(* Logix 5000 project; controller V16_L55_Blank vendor 1 type 14 code 51 rev 16.2; software revision 16.04; part 2 of 5 *)
(* tags used below, declared in another part *)
   ConnectionOutput : INT[248];
   StoppedTimer : TIMER;
   ProveEnabled : BOOL;
   NotStoppedTimer : TIMER;
   CycleCounterPreviousStopped : INT;
   MJFAULTS : DINT[12];
   ForceReset : BOOL;
   AvoidBufferOverflowFault : DINT;   // Need this to prevent Overflow Minor Fault
   AOI56EAFC : AOI56EAFC;
(* AOI56EAFC, continued *)

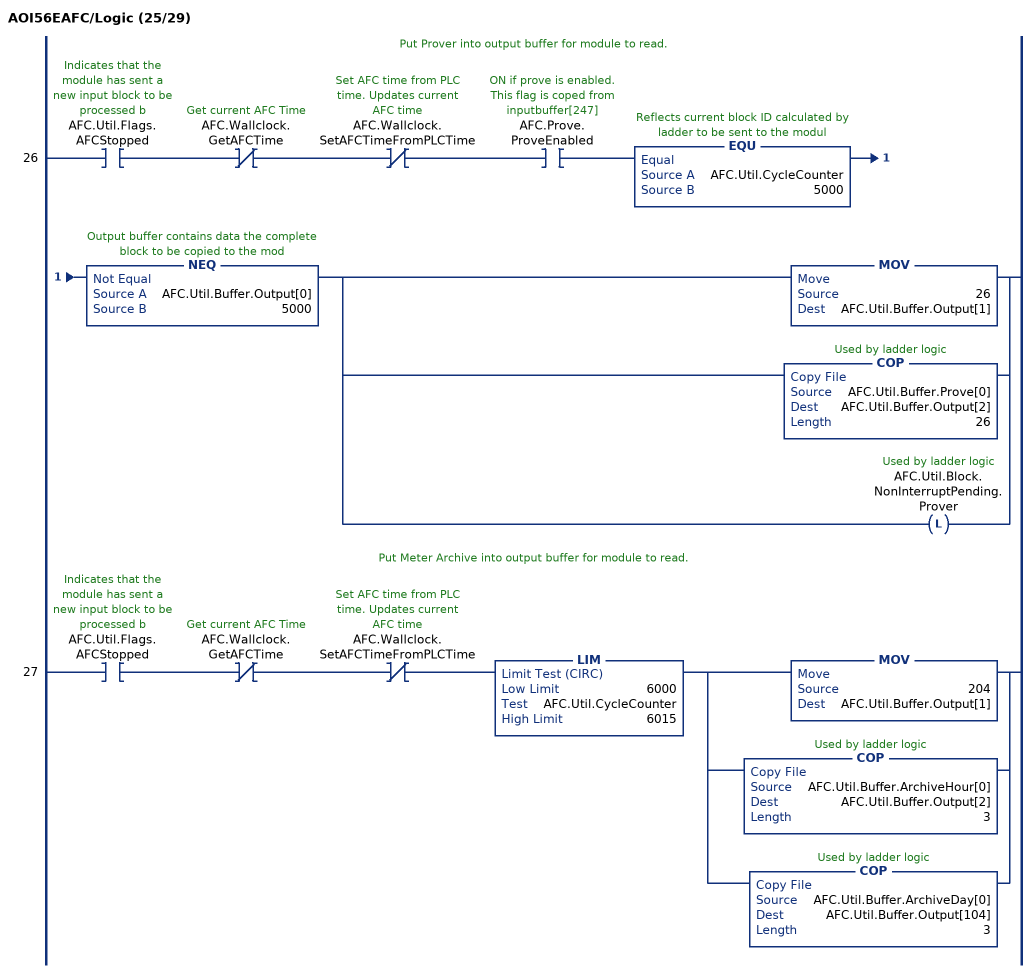
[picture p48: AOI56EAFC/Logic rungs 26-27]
   // Put Prover into output buffer for module to read.
   26: XIC(AFC.Util.Flags.AFCStopped)XIO(AFC.Wallclock.GetAFCTime)XIO(AFC.Wallclock.SetAFCTimeFromPLCTime)XIC(AFC.Prove.ProveEnabled)EQU(AFC.Util.CycleCounter,5000)NEQ(AFC.Util.Buffer.Output[0],5000)[MOV(26,AFC.Util.Buffer.Output[1]) ,COP(AFC.Util.Buffer.Prove[0],AFC.Util.Buffer.Output[2],26) ,OTL(AFC.Util.Block.NonInterruptPending.Prover) ];
   // Put Meter Archive into output buffer for module to read.
   27: XIC(AFC.Util.Flags.AFCStopped)XIO(AFC.Wallclock.GetAFCTime)XIO(AFC.Wallclock.SetAFCTimeFromPLCTime)LIM(6000,AFC.Util.CycleCounter,6015)[MOV(204,AFC.Util.Buffer.Output[1]) ,COP(AFC.Util.Buffer.ArchiveHour[0],AFC.Util.Buffer.Output[2],3) ,COP(AFC.Util.Buffer.ArchiveDay[0],AFC.Util.Buffer.Output[104],3) ];
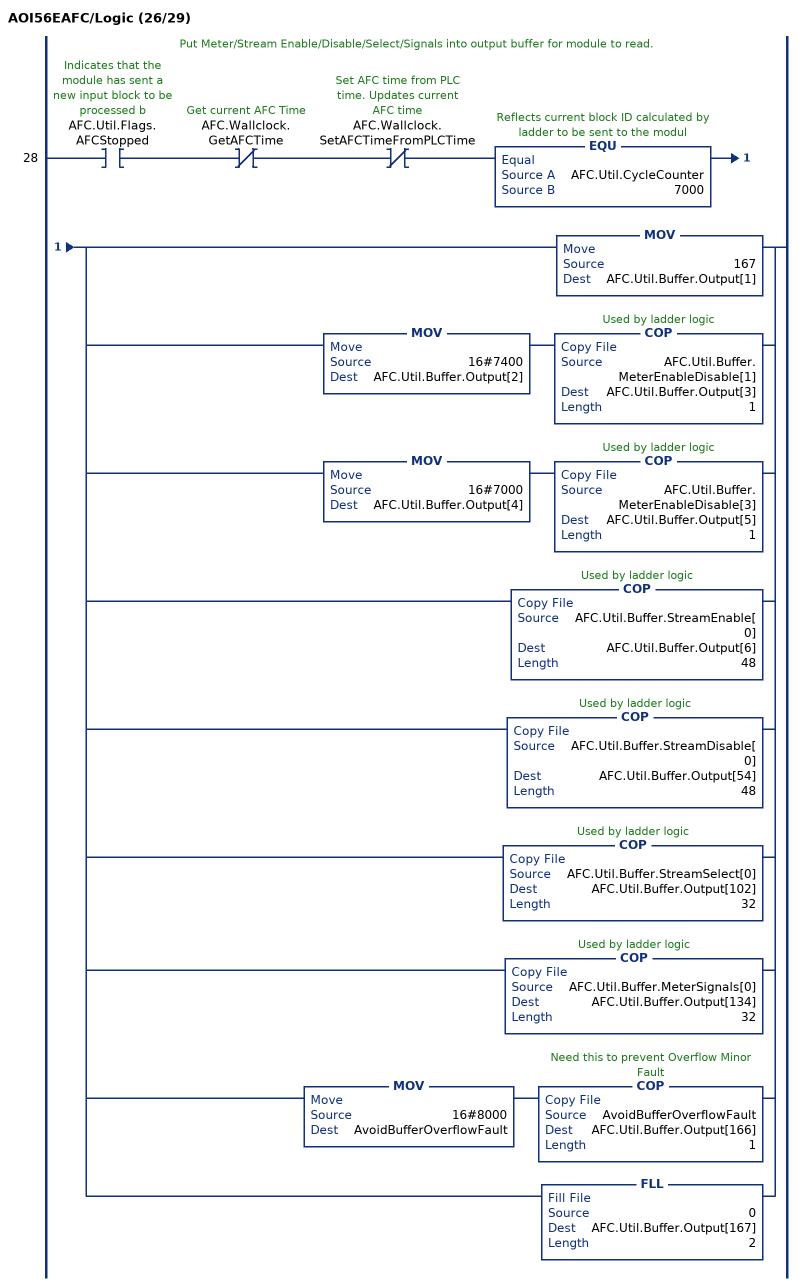
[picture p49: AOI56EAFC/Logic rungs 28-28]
   // Put Meter/Stream Enable/Disable/Select/Signals into output buffer for module to read.
   28: XIC(AFC.Util.Flags.AFCStopped)XIO(AFC.Wallclock.GetAFCTime)XIO(AFC.Wallclock.SetAFCTimeFromPLCTime)EQU(AFC.Util.CycleCounter,7000)[MOV(167,AFC.Util.Buffer.Output[1]) ,MOV(16#7400,AFC.Util.Buffer.Output[2]) COP(AFC.Util.Buffer.MeterEnableDisable[1],AFC.Util.Buffer.Output[3],1) ,MOV(16#7000,AFC.Util.Buffer.Output[4]) COP(AFC.Util.Buffer.MeterEnableDisable[3],AFC.Util.Buffer.Output[5],1) ,COP(AFC.Util.Buffer.StreamEnable[0],AFC.Util.Buffer.Output[6],48) ,COP(AFC.Util.Buffer.StreamDisable[0],AFC.Util.Buffer.Output[54],48) ,COP(AFC.Util.Buffer.StreamSelect[0],AFC.Util.Buffer.Output[102],32) ,COP(AFC.Util.Buffer.MeterSignals[0],AFC.Util.Buffer.Output[134],32) ,[MOV(16#8000,AvoidBufferOverflowFault) COP(AvoidBufferOverflowFault,AFC.Util.Buffer.Output[166],1) ,FLL(0,AFC.Util.Buffer.Output[167],2) ] ];
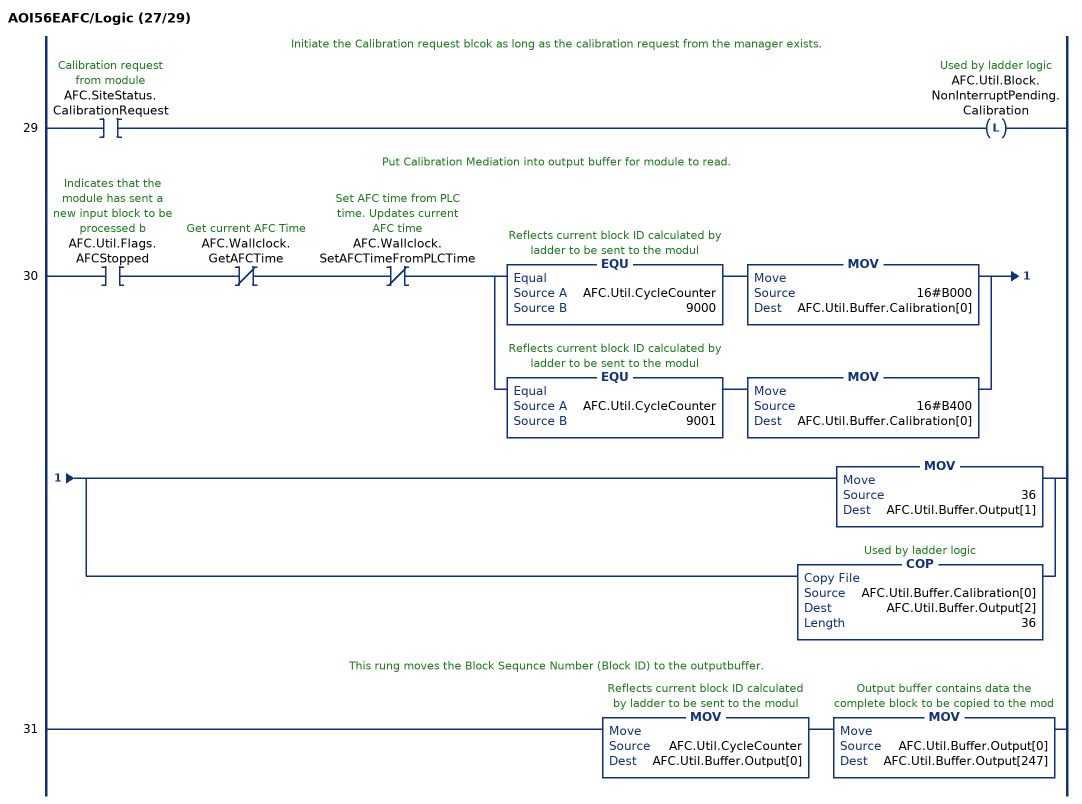
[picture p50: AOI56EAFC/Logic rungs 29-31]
   // Initiate the Calibration request blcok as long as the calibration request from the manager exists.
   29: XIC(AFC.SiteStatus.CalibrationRequest)OTL(AFC.Util.Block.NonInterruptPending.Calibration);
   // Put Calibration Mediation into output buffer for module to read.
   30: XIC(AFC.Util.Flags.AFCStopped)XIO(AFC.Wallclock.GetAFCTime)XIO(AFC.Wallclock.SetAFCTimeFromPLCTime)[EQU(AFC.Util.CycleCounter,9000) MOV(16#B000,AFC.Util.Buffer.Calibration[0]) ,EQU(AFC.Util.CycleCounter,9001) MOV(16#B400,AFC.Util.Buffer.Calibration[0]) ][MOV(36,AFC.Util.Buffer.Output[1]) ,COP(AFC.Util.Buffer.Calibration[0],AFC.Util.Buffer.Output[2],36) ];
   // This rung moves the Block Sequnce Number (Block ID) to the outputbuffer.
   31: MOV(AFC.Util.CycleCounter,AFC.Util.Buffer.Output[0])MOV(AFC.Util.Buffer.Output[0],AFC.Util.Buffer.Output[247]);
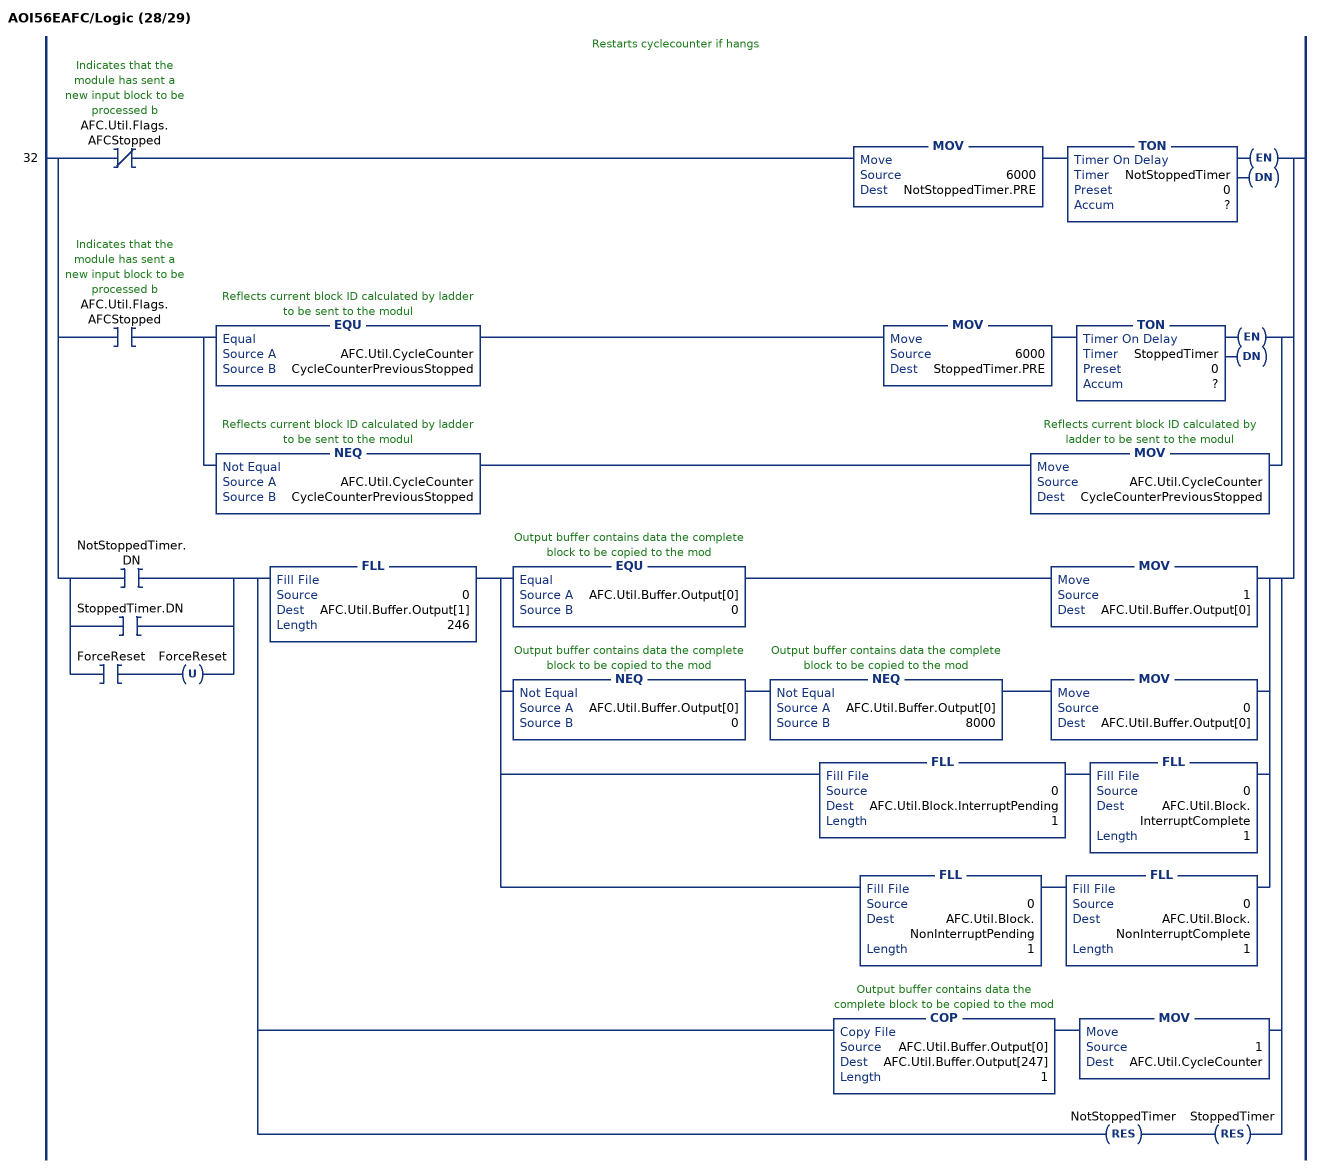
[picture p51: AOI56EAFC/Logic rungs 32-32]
   // Restarts cyclecounter if hangs
   32: [XIO(AFC.Util.Flags.AFCStopped) MOV(6000,NotStoppedTimer.PRE) TON(NotStoppedTimer,?,?) ,XIC(AFC.Util.Flags.AFCStopped) [EQU(AFC.Util.CycleCounter,CycleCounterPreviousStopped) MOV(6000,StoppedTimer.PRE) TON(StoppedTimer,?,?) ,NEQ(AFC.Util.CycleCounter,CycleCounterPreviousStopped) MOV(AFC.Util.CycleCounter,CycleCounterPreviousStopped) ] ,[[XIC(NotStoppedTimer.DN) ,XIC(StoppedTimer.DN) ] ,XIC(ForceReset) OTU(ForceReset) ] [FLL(0,AFC.Util.Buffer.Output[1],246) [EQU(AFC.Util.Buffer.Output[0],0) MOV(1,AFC.Util.Buffer.Output[0]) ,NEQ(AFC.Util.Buffer.Output[0],0) NEQ(AFC.Util.Buffer.Output[0],8000) MOV(0,AFC.Util.Buffer.Output[0]) ,FLL(0,AFC.Util.Block.InterruptPending,1) FLL(0,AFC.Util.Block.InterruptComplete,1) ,FLL(0,AFC.Util.Block.NonInterruptPending,1) FLL(0,AFC.Util.Block.NonInterruptComplete,1) ] ,COP(AFC.Util.Buffer.Output[0],AFC.Util.Buffer.Output[247],1) MOV(1,AFC.Util.CycleCounter) ,RES(NotStoppedTimer) RES(StoppedTimer) ] ];
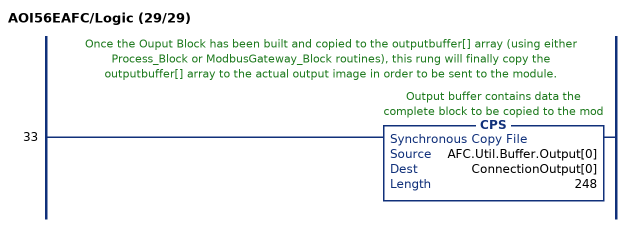
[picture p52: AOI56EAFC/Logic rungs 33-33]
   // Once the Ouput Block has been built and copied to the outputbuffer[] array (using either Process_Block or ModbusGateway_Block routines), this rung will finally copy the outputbuffer[] array to the actual output image in order to be sent to the module.
   33: CPS(AFC.Util.Buffer.Output[0],ConnectionOutput[0],248);
END_ROUTINE

ROUTINE Prescan   (* ladder *)
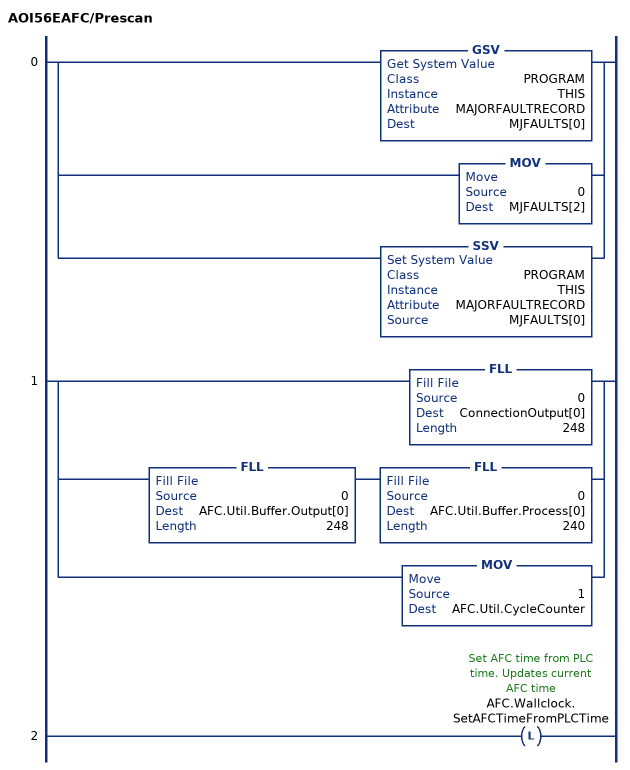
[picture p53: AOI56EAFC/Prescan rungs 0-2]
   0: [GSV(PROGRAM,THIS,MAJORFAULTRECORD,MJFAULTS[0]) ,MOV(0,MJFAULTS[2]) ,SSV(PROGRAM,THIS,MAJORFAULTRECORD,MJFAULTS[0]) ];
   1: [FLL(0,ConnectionOutput[0],248) ,FLL(0,AFC.Util.Buffer.Output[0],248) FLL(0,AFC.Util.Buffer.Process[0],240) ,MOV(1,AFC.Util.CycleCounter) ];
   2: OTL(AFC.Wallclock.SetAFCTimeFromPLCTime);
END_ROUTINE
END_ADD_ON_INSTRUCTION

ADD_ON_INSTRUCTION AOI56EAFCMeterDifferentialGas   (* revision 1.8, ExecutePrescan *)
// Add-On instruction for the MVI56E-AFC.
// Differential Gas Meter
// Revision note:
// Corrected/Reverted ProcessInputBlockID Tag Data Type from INT to DINT.
// Help:
// Compatible with version 4.03 of MVI56E-AFC firmware or higher.
// v1.2: Remove Calculation Results. Add Backplane Return. Add Stale Data
// v1.3: Added Flow Rate Process Input and Flow Rate Alarm Controller Tags for Flow Rate Devices (and not just for Differential Pressure)
// v1.4: Addition of default process input backplane return data mapping.
// v1.5: Made correlation changes between the Module Archive Default UDTs and the AOI Archive Default UDTs.
// v1.6: Made changes to the Flow Rate Primary Input Block ID Insertion in Rung 8 (Removed +1),
// Modified ProcessInputBlockID Tag Data Type from DINT to INT. and modified ModbusGatewayConfig UDT StartRegister Tag Data Type from INT to DINT.
// v1.7:  Updated Tags names AFCMeterXXYYYYYY.BackPlaneReturn.ProcessInputs to AFCMeterXXYYYYYY.BackPlaneReturn.Standard and AFCMeterXXYYYYYY.BackPlaneReturn.ComponentAnalysis
//  to AFCMeterXXYYYYYY.BackPlaneReturn.Extended
// v1.8:  Corrected/Reverted ProcessInputBlockID Tag Data Type from INT to DINT.
VAR_IN_OUT
   ConnectionInput : INT[250]; {required}
   AFC : AFCEModuleDef; {required}
   AFCMeter : AFCEMeterDifferentialGas; {required}
END_VAR
VAR_INPUT
   MeterNumber : SINT; {required}   // Meter Number Set to a number between 1 and 16
END_VAR
VAR
   TimestampBuffer : DINT;
   StreamSelectedShift : DINT;
   StreamSelectBuffer : INT;
   EnabledStatusBuffer : INT;
   StreamSelectBlockID : DINT;
   StreamNumberShift : DINT;
   StreamErrorBuffer : DINT;
   StreamEnableBlockID : DINT;
   StreamEnableBitPosition : DINT;
   StreamDisableBlockID : DINT;
   ProfileBuffer : SINT[2];
   ProcessInputBlockID : DINT;
   CalibrationHandleBuffer : INT;
   AnalysisGroupBitPosition : INT;
   ProcessAlarmShifter : DINT;
   ProcessAlarmBuffer : DINT;
   MeterSignaltBlockID : DINT;
   MeterNumberShift : DINT;
   MeterNumberBitPostition : DINT;
   Inputbuffer : INT[250];
   CurrentHourlyAgeONS : BOOL;
   CurrentHourlyAge : DINT;
   CurrentDailyAgeONS : BOOL;
   CurrentDailyAge : DINT;
   ClearMeterSignal : BOOL;   // Repeat the meter signal block with cleared signal bits. This allows repeat triggering of a signal.
   CalibrationMeterNumberBuffer : DINT;
   CalibrationMediationPending : BOOL;
   CalibrationInputScalingIndex : DINT;
   AnalysisErrorBuffer : INT;
   ArchiveStream : DINT;
   ArchiveMeterStatusRaw : DINT;
   ArchiveMeterStatusActiveStream : DINT;
   ArchiveHourlyRawSize : DINT;
   ArchiveHourlyOffset : DINT;
   ArchiveHourlyDefaultSize : DINT;
   ArchiveDailyRawSize : DINT;
   ArchiveDailyOffset : DINT;
   ArchiveDailyDefaultSize : DINT;
   ArchiveCompleteBitCheck : DINT;
   ArchiveBlockID : DINT;
   AnalysisGroupShift : DINT;
   AnalysisCompleteBitCheck : DINT;
   AnalysisBufferOffset : DINT;
   AnalysisBlockID : DINT;
   AFCStopped : BOOL;
   AFCInputDataAvailable : BOOL;
END_VAR

ROUTINE Logic   (* ladder *)
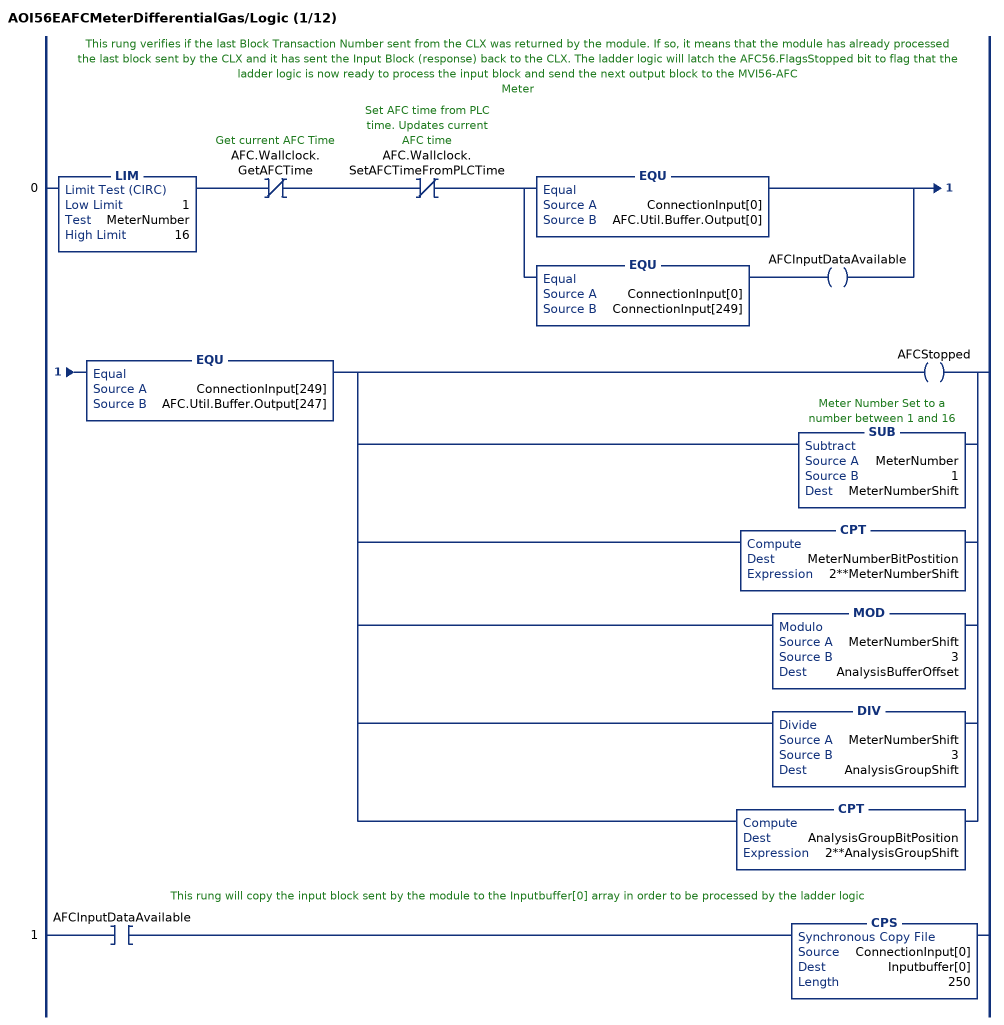
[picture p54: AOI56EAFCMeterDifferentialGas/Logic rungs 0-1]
   // This rung verifies if the last Block Transaction Number sent from the CLX was returned by the module. If so, it means that the module has already processed the last block sent by the CLX and it has sent the Input Block (response) back to the CLX. The ladder logic will latch the AFC56.FlagsStopped bit to flag that the ladder logic is now ready to process the input block and send the next output block to the MVI56-AFC
   // Meter
   0: LIM(1,MeterNumber,16)XIO(AFC.Wallclock.GetAFCTime)XIO(AFC.Wallclock.SetAFCTimeFromPLCTime)[EQU(ConnectionInput[0],AFC.Util.Buffer.Output[0]) ,EQU(ConnectionInput[0],ConnectionInput[249]) OTE(AFCInputDataAvailable) ]EQU(ConnectionInput[249],AFC.Util.Buffer.Output[247])[OTE(AFCStopped) ,SUB(MeterNumber,1,MeterNumberShift) ,CPT(MeterNumberBitPostition,2**MeterNumberShift) ,MOD(MeterNumberShift,3,AnalysisBufferOffset) ,DIV(MeterNumberShift,3,AnalysisGroupShift) ,CPT(AnalysisGroupBitPosition,2**AnalysisGroupShift) ];
   // This rung will copy the input block sent by the module to the Inputbuffer[0] array in order to be processed by the ladder logic
   1: XIC(AFCInputDataAvailable)CPS(ConnectionInput[0],Inputbuffer[0],250);
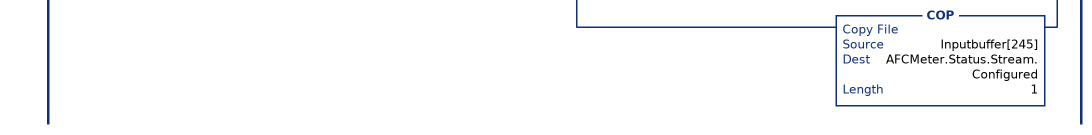
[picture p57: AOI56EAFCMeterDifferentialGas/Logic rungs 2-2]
   // Read process input backplane return and
   // meter profile (when block ID matches meter number).
   2: XIC(AFCInputDataAvailable)LIM(1,Inputbuffer[0],16)[COP(Inputbuffer[3+MeterNumberShift*15],AFCMeter.BackPlaneReturn.StandardRaw[0],14) ,COP(AFCMeter.BackPlaneReturn.StandardRaw[0],AFCMeter.BackPlaneReturn.StandardDefault,1) ,COP(Inputbuffer[247],AFC.SiteStatus,1) ,COP(Inputbuffer[248],AFC.MeterAlarms,1) ,EQU(Inputbuffer[0],MeterNumber) [COP(Inputbuffer[243],ProfileBuffer[0],2) ,[XIC(ProfileBuffer[0].0) OTL(AFCMeter.Status.Meter.EnableAlarm) ,XIO(ProfileBuffer[0].0) OTU(AFCMeter.Status.Meter.EnableAlarm) ] ,[XIC(ProfileBuffer[0].1) OTL(AFCMeter.Status.Meter.Enabled) ,XIO(ProfileBuffer[0].1) OTU(AFCMeter.Status.Meter.Enabled) ] ,[[XIC(ProfileBuffer[0].4) OTL(AFCMeter.Profile.MeterType) ,XIO(ProfileBuffer[0].4) OTU(AFCMeter.Profile.MeterType) ] ,[XIC(ProfileBuffer[0].5) OTL(AFCMeter.Profile.ProductGroup) ,XIO(ProfileBuffer[0].5) OTU(AFCMeter.Profile.ProductGroup) ] ,[XIC(ProfileBuffer[0].6) OTL(AFCMeter.Profile.PrimaryInput) ,XIO(ProfileBuffer[0].6) OTU(AFCMeter.Profile.PrimaryInput) ] ] ,[[XIC(ProfileBuffer[0].4) ,XIC(ProfileBuffer[0].5) ] OTL(AFCMeter.Profile.AOIMismatch) ,XIO(ProfileBuffer[0].4) XIO(ProfileBuffer[0].5) OTU(AFCMeter.Profile.AOIMismatch) ] ,MVM(ProfileBuffer[1],16#1F,ProfileBuffer[1]) ADD(ProfileBuffer[1],1,AFCMeter.Status.Stream.Active) ,COP(Inputbuffer[244],AFCMeter.Status.Stream.Enabled,1) ,COP(Inputbuffer[245],AFCMeter.Status.Stream.Configured,1) ] ];
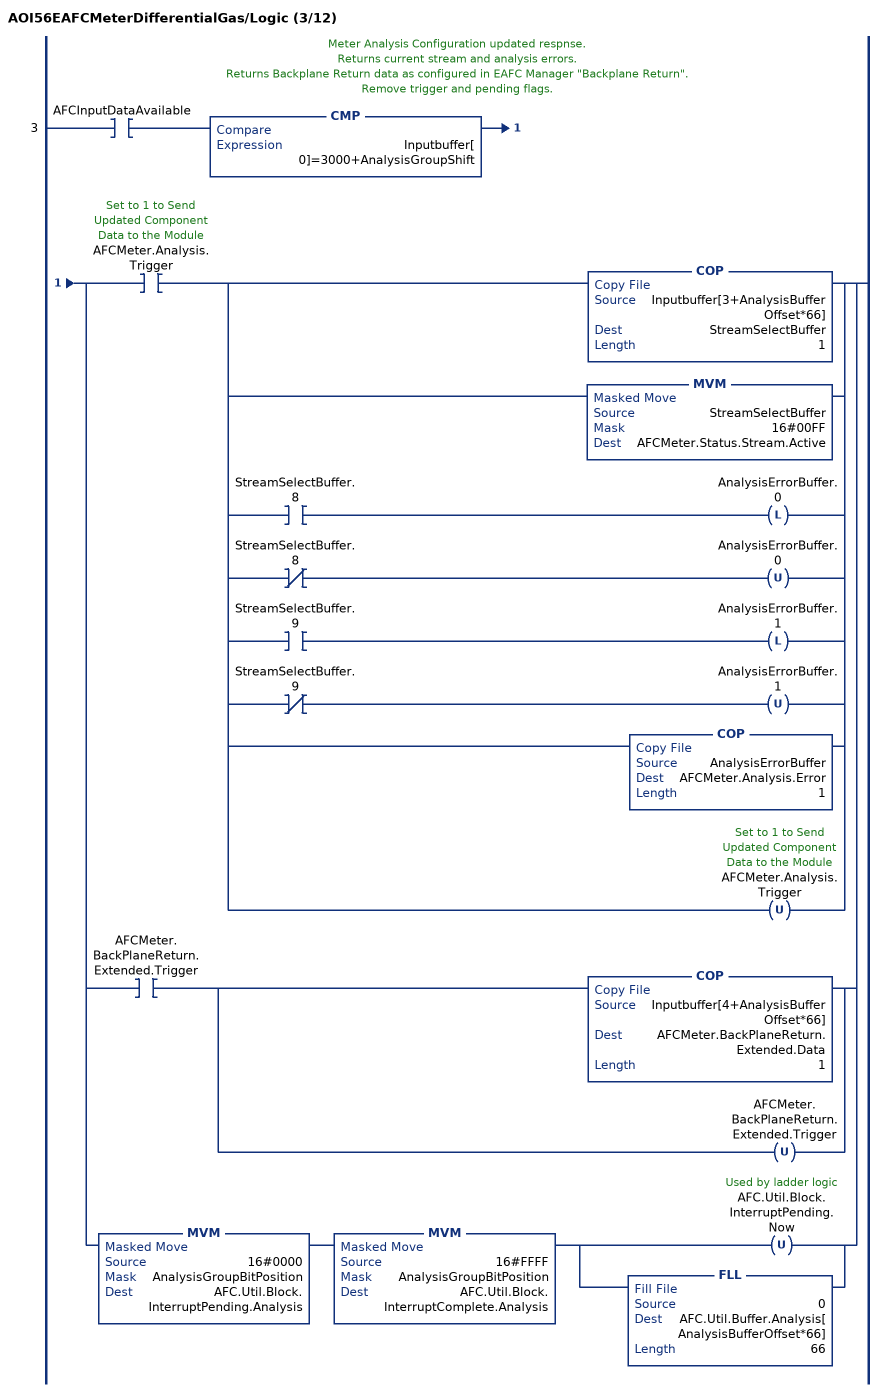
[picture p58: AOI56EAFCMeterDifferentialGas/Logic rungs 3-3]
   // Meter Analysis Configuration updated respnse.
   // Returns current stream and analysis errors.
   // Returns Backplane Return data as configured in EAFC Manager "Backplane Return".
   // Remove trigger and pending flags.
   3: XIC(AFCInputDataAvailable)CMP(Inputbuffer[0]=3000+AnalysisGroupShift)[XIC(AFCMeter.Analysis.Trigger) [COP(Inputbuffer[3+AnalysisBufferOffset*66],StreamSelectBuffer,1) ,MVM(StreamSelectBuffer,16#00FF,AFCMeter.Status.Stream.Active) ,[XIC(StreamSelectBuffer.8) OTL(AnalysisErrorBuffer.0) ,XIO(StreamSelectBuffer.8) OTU(AnalysisErrorBuffer.0) ] ,[XIC(StreamSelectBuffer.9) OTL(AnalysisErrorBuffer.1) ,XIO(StreamSelectBuffer.9) OTU(AnalysisErrorBuffer.1) ] ,COP(AnalysisErrorBuffer,AFCMeter.Analysis.Error,1) ,OTU(AFCMeter.Analysis.Trigger) ] ,XIC(AFCMeter.BackPlaneReturn.Extended.Trigger) [COP(Inputbuffer[4+AnalysisBufferOffset*66],AFCMeter.BackPlaneReturn.Extended.Data,1) ,OTU(AFCMeter.BackPlaneReturn.Extended.Trigger) ] ,MVM(16#0000,AnalysisGroupBitPosition,AFC.Util.Block.InterruptPending.Analysis) MVM(16#FFFF,AnalysisGroupBitPosition,AFC.Util.Block.InterruptComplete.Analysis) [OTU(AFC.Util.Block.InterruptPending.Now) ,FLL(0,AFC.Util.Buffer.Analysis[AnalysisBufferOffset*66],66) ] ];
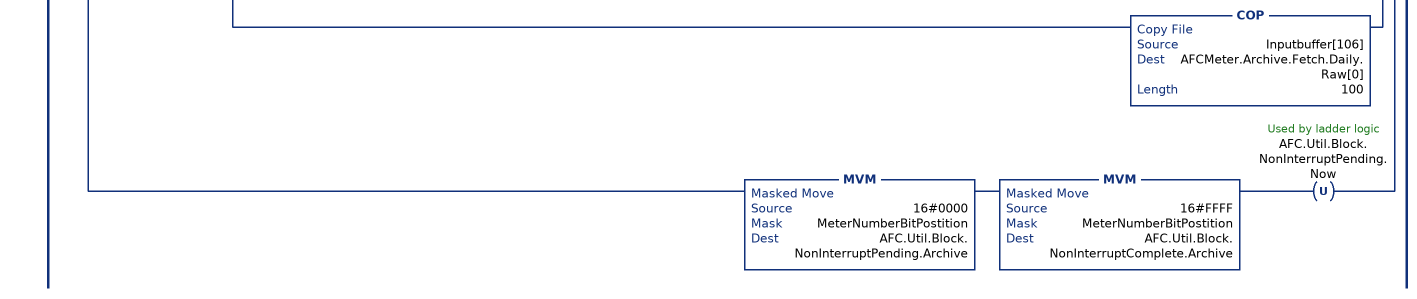
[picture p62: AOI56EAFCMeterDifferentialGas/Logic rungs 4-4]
   // Archive Fetch to default and raw UDT's.
   // Get archive alarms.
   // Remove trigger and pending flags.
   4: XIC(AFCInputDataAvailable)CMP(Inputbuffer[0]=6000+MeterNumberShift)[XIC(AFCMeter.Archive.Fetch.Hourly.Trigger) [OTU(AFCMeter.Archive.Fetch.Hourly.Trigger) ,[[XIC(Inputbuffer[3].0) OTL(AFCMeter.Archive.Fetch.Hourly.Error.ArchiveSelectionInvalid) ,XIO(Inputbuffer[3].0) OTU(AFCMeter.Archive.Fetch.Hourly.Error.ArchiveSelectionInvalid) ] ,[XIC(Inputbuffer[3].1) OTL(AFCMeter.Archive.Fetch.Hourly.Error.AgeOutsideSize) ,XIO(Inputbuffer[3].1) OTU(AFCMeter.Archive.Fetch.Hourly.Error.AgeOutsideSize) ] ,[XIC(Inputbuffer[3].2) OTL(AFCMeter.Archive.Fetch.Hourly.Error.ArchiveNeverWritten) ,XIO(Inputbuffer[3].2) OTU(AFCMeter.Archive.Fetch.Hourly.Error.ArchiveNeverWritten) ] ] ,COP(Inputbuffer[4],AFCMeter.Archive.Fetch.Hourly.Default.ClosingTimestamp,1) ,COP(Inputbuffer[6],AFCMeter.Archive.Fetch.Hourly.Default.CumulativeActiveStreams,1) ,COP(Inputbuffer[7],ArchiveMeterStatusActiveStream,1) [MVM(ArchiveMeterStatusActiveStream,16#0000000F,ArchiveStream) ADD(ArchiveStream,1,AFCMeter.Archive.Fetch.Hourly.Default.CurrentActiveStream) ,MVM(ArchiveMeterStatusActiveStream,16#0000FF00,ArchiveMeterStatusRaw) DIV(ArchiveMeterStatusRaw,256,ArchiveMeterStatusRaw) COP(ArchiveMeterStatusRaw,AFCMeter.Archive.Fetch.Hourly.Default.MeterStatus,1) ] ,COP(Inputbuffer[8],AFCMeter.Archive.Fetch.Hourly.Default.FlowingPeriod,48) ,COP(Inputbuffer[4],AFCMeter.Archive.Fetch.Hourly.Raw[0],100) ] ,XIC(AFCMeter.Archive.Fetch.Daily.Trigger) [OTU(AFCMeter.Archive.Fetch.Daily.Trigger) ,[[XIC(Inputbuffer[105].0) OTL(AFCMeter.Archive.Fetch.Daily.Error.ArchiveSelectionInvalid) ,XIO(Inputbuffer[105].0) OTU(AFCMeter.Archive.Fetch.Daily.Error.ArchiveSelectionInvalid) ] ,[XIC(Inputbuffer[105].1) OTL(AFCMeter.Archive.Fetch.Daily.Error.AgeOutsideSize) ,XIO(Inputbuffer[105].1) OTU(AFCMeter.Archive.Fetch.Daily.Error.AgeOutsideSize) ] ,[XIC(Inputbuffer[105].2) OTL(AFCMeter.Archive.Fetch.Daily.Error.ArchiveNeverWritten) ,XIO(Inputbuffer[105].2) OTU(AFCMeter.Archive.Fetch.Daily.Error.ArchiveNeverWritten) ] ] ,COP(Inputbuffer[106],AFCMeter.Archive.Fetch.Daily.Default.ClosingTimestamp,1) ,COP(Inputbuffer[108],AFCMeter.Archive.Fetch.Daily.Default.CumulativeActiveStreams,1) ,COP(Inputbuffer[109],ArchiveMeterStatusActiveStream,1) [MVM(ArchiveMeterStatusActiveStream,16#0000000F,ArchiveStream) ADD(ArchiveStream,1,AFCMeter.Archive.Fetch.Daily.Default.CurrentActiveStream) ,MVM(ArchiveMeterStatusActiveStream,16#0000FF00,ArchiveMeterStatusRaw) DIV(ArchiveMeterStatusRaw,256,ArchiveMeterStatusRaw) COP(ArchiveMeterStatusRaw,AFCMeter.Archive.Fetch.Daily.Default.MeterStatus,1) ] ,COP(Inputbuffer[110],AFCMeter.Archive.Fetch.Daily.Default.FlowingPeriod,48) ,COP(Inputbuffer[106],AFCMeter.Archive.Fetch.Daily.Raw[0],100) ] ,MVM(16#0000,MeterNumberBitPostition,AFC.Util.Block.NonInterruptPending.Archive) MVM(16#FFFF,MeterNumberBitPostition,AFC.Util.Block.NonInterruptComplete.Archive) OTU(AFC.Util.Block.NonInterruptPending.Now) ];
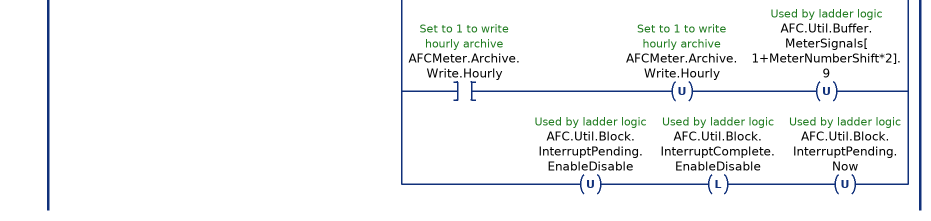
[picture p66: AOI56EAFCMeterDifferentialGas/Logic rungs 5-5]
   // Meter status and stream status.
   // Remove trigger and pending flags.
   5: XIC(AFCInputDataAvailable)EQU(Inputbuffer[0],7000)[[MVM(Inputbuffer[3],MeterNumberBitPostition,EnabledStatusBuffer) ,[NEQ(EnabledStatusBuffer,0) OTL(AFCMeter.Status.Meter.Enabled) ,EQU(EnabledStatusBuffer,0) OTU(AFCMeter.Status.Meter.Enabled) ] ,OTU(AFCMeter.Control.Meter.Enable) MVM(16#0000,MeterNumberBitPostition,AFC.Util.Buffer.MeterEnableDisable[1]) ,OTU(AFCMeter.Control.Meter.Disable) MVM(16#0000,MeterNumberBitPostition,AFC.Util.Buffer.MeterEnableDisable[3]) ] ,[XIC(AFCMeter.Control.Stream.EnableSelected) [COP(Inputbuffer[7+MeterNumberShift*3],AFCMeter.Status.Stream.Enabled,1) ,COP(Inputbuffer[8+MeterNumberShift*3],AFCMeter.Status.Stream.Configured,1) ,OTU(AFCMeter.Control.Stream.EnableSelected) OTU(AFCMeter.Control.Stream.DisableSelected) ] ,XIC(AFCMeter.Control.Stream.DisableSelected) [COP(Inputbuffer[55+MeterNumberShift*3],AFCMeter.Status.Stream.Enabled,1) ,COP(Inputbuffer[56+MeterNumberShift*3],AFCMeter.Status.Stream.Configured,1) ,OTU(AFCMeter.Control.Stream.EnableSelected) OTU(AFCMeter.Control.Stream.DisableSelected) ] ] ,[OTU(AFCMeter.Control.Stream.SetSelectedToActive) ,COP(Inputbuffer[103+MeterNumberShift*2],StreamSelectBuffer,1) ,[XIC(StreamSelectBuffer.8) OTL(StreamErrorBuffer.0) ,XIO(StreamSelectBuffer.8) OTU(StreamErrorBuffer.0) ] ,[XIC(StreamSelectBuffer.9) OTL(StreamErrorBuffer.1) ,XIO(StreamSelectBuffer.9) OTU(StreamErrorBuffer.1) ] ,[XIC(StreamSelectBuffer.10) OTL(StreamErrorBuffer.2) ,XIO(StreamSelectBuffer.10) OTU(StreamErrorBuffer.2) ] ,[XIC(StreamSelectBuffer.11) OTL(StreamErrorBuffer.3) ,XIO(StreamSelectBuffer.11) OTU(StreamErrorBuffer.3) ] ,MVM(StreamSelectBuffer,16#000F,StreamSelectedShift) ADD(StreamSelectedShift,1,AFCMeter.Status.Stream.Active) ,COP(StreamErrorBuffer,AFCMeter.Status.Stream.EnableAlarm,1) ] ,[XIC(AFCMeter.Control.ResetAccumulators.ResetAccumulator1) OTU(AFCMeter.Control.ResetAccumulators.ResetAccumulator1) OTU(AFC.Util.Buffer.MeterSignals[1+MeterNumberShift*2].4) ,XIC(AFCMeter.Control.ResetAccumulators.ResetAccumulator2) OTU(AFCMeter.Control.ResetAccumulators.ResetAccumulator2) OTU(AFC.Util.Buffer.MeterSignals[1+MeterNumberShift*2].5) ,XIC(AFCMeter.Control.ResetAccumulators.ResetAccumulator3) OTU(AFCMeter.Control.ResetAccumulators.ResetAccumulator3) OTU(AFC.Util.Buffer.MeterSignals[1+MeterNumberShift*2].6) ,XIC(AFCMeter.Control.ResetAccumulators.ResetAccumulator4) OTU(AFCMeter.Control.ResetAccumulators.ResetAccumulator4) OTU(AFC.Util.Buffer.MeterSignals[1+MeterNumberShift*2].7) ,XIC(AFCMeter.Archive.Write.Daily) OTU(AFCMeter.Archive.Write.Daily) OTU(AFC.Util.Buffer.MeterSignals[1+MeterNumberShift*2].8) ,XIC(AFCMeter.Archive.Write.Hourly) OTU(AFCMeter.Archive.Write.Hourly) OTU(AFC.Util.Buffer.MeterSignals[1+MeterNumberShift*2].9) ] ,OTU(AFC.Util.Block.InterruptPending.EnableDisable) OTL(AFC.Util.Block.InterruptComplete.EnableDisable) OTU(AFC.Util.Block.InterruptPending.Now) ];
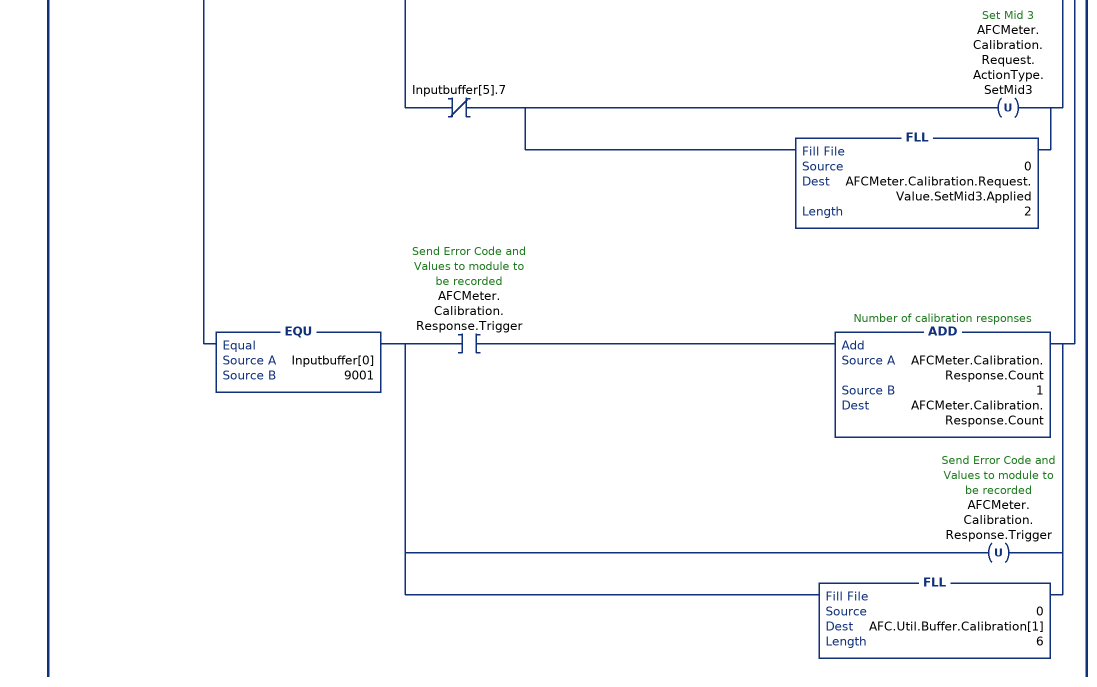
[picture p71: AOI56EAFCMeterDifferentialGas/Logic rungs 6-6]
   // Meter transmitter calibration.
   6: XIC(AFCInputDataAvailable)[EQU(Inputbuffer[0],9000) ,EQU(Inputbuffer[0],9001) ][MVM(Inputbuffer[3],16#0F00,CalibrationMeterNumberBuffer) ,DIV(CalibrationMeterNumberBuffer,16#100,CalibrationMeterNumberBuffer) ]EQU(CalibrationMeterNumberBuffer,MeterNumberShift)XIO(Inputbuffer[3].14)[EQU(Inputbuffer[0],9000) [XIO(CalibrationMediationPending) ADD(AFCMeter.Calibration.Request.Count,1,AFCMeter.Calibration.Request.Count) ,OTL(CalibrationMediationPending) [COP(Inputbuffer[3],CalibrationHandleBuffer,1) ,MVM(CalibrationHandleBuffer,16#000F,CalibrationInputScalingIndex) ] ,[EQU(CalibrationInputScalingIndex,0) [OTL(AFCMeter.Calibration.Request.ProcessVariable.DifferentialPressure) ,OTU(AFCMeter.Calibration.Request.ProcessVariable.Temperature) ,OTU(AFCMeter.Calibration.Request.ProcessVariable.Pressure) ] ,EQU(CalibrationInputScalingIndex,1) [OTL(AFCMeter.Calibration.Request.ProcessVariable.Temperature) ,OTU(AFCMeter.Calibration.Request.ProcessVariable.DifferentialPressure) ,OTU(AFCMeter.Calibration.Request.ProcessVariable.Pressure) ] ,EQU(CalibrationInputScalingIndex,2) [OTL(AFCMeter.Calibration.Request.ProcessVariable.Pressure) ,OTU(AFCMeter.Calibration.Request.ProcessVariable.DifferentialPressure) ,OTU(AFCMeter.Calibration.Request.ProcessVariable.Temperature) ] ] ,[[XIC(Inputbuffer[5].2) [OTL(AFCMeter.Calibration.Request.ActionType.ZeroShift) ,COP(Inputbuffer[6],AFCMeter.Calibration.Request.Value.ZeroShift.Applied,2) ] ,XIO(Inputbuffer[5].2) [OTU(AFCMeter.Calibration.Request.ActionType.ZeroShift) ,FLL(0,AFCMeter.Calibration.Request.Value.ZeroShift.Applied,2) ] ] ,[XIC(Inputbuffer[5].3) [OTL(AFCMeter.Calibration.Request.ActionType.SetZero) ,COP(Inputbuffer[10],AFCMeter.Calibration.Request.Value.SetZero.Applied,2) ] ,XIO(Inputbuffer[5].3) [OTU(AFCMeter.Calibration.Request.ActionType.SetZero) ,FLL(0,AFCMeter.Calibration.Request.Value.SetZero.Applied,2) ] ] ,[XIC(Inputbuffer[5].4) [OTL(AFCMeter.Calibration.Request.ActionType.SetSpan) ,COP(Inputbuffer[14],AFCMeter.Calibration.Request.Value.SetSpan.Applied,2) ] ,XIO(Inputbuffer[5].4) [OTU(AFCMeter.Calibration.Request.ActionType.SetSpan) ,FLL(0,AFCMeter.Calibration.Request.Value.SetSpan.Applied,2) ] ] ,[XIC(Inputbuffer[5].5) [OTL(AFCMeter.Calibration.Request.ActionType.SetMid1) ,COP(Inputbuffer[18],AFCMeter.Calibration.Request.Value.SetMid1.Applied,2) ] ,XIO(Inputbuffer[5].5) [OTU(AFCMeter.Calibration.Request.ActionType.SetMid1) ,FLL(0,AFCMeter.Calibration.Request.Value.SetMid1.Applied,2) ] ] ,[XIC(Inputbuffer[5].6) [OTL(AFCMeter.Calibration.Request.ActionType.SetMid2) ,COP(Inputbuffer[22],AFCMeter.Calibration.Request.Value.SetMid2.Applied,2) ] ,XIO(Inputbuffer[5].6) [OTU(AFCMeter.Calibration.Request.ActionType.SetMid2) ,FLL(0,AFCMeter.Calibration.Request.Value.SetMid2.Applied,2) ] ] ,[XIC(Inputbuffer[5].7) [OTL(AFCMeter.Calibration.Request.ActionType.SetMid3) ,COP(Inputbuffer[26],AFCMeter.Calibration.Request.Value.SetMid3.Applied,2) ] ,XIO(Inputbuffer[5].7) [OTU(AFCMeter.Calibration.Request.ActionType.SetMid3) ,FLL(0,AFCMeter.Calibration.Request.Value.SetMid3.Applied,2) ] ] ] ] ,EQU(Inputbuffer[0],9001) [XIC(AFCMeter.Calibration.Response.Trigger) ADD(AFCMeter.Calibration.Response.Count,1,AFCMeter.Calibration.Response.Count) ,OTU(AFCMeter.Calibration.Response.Trigger) ,FLL(0,AFC.Util.Buffer.Calibration[1],6) ] ];
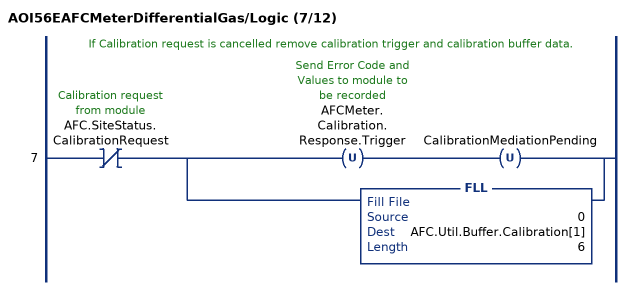
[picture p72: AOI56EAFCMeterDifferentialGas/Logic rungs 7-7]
   // If Calibration request is cancelled remove calibration trigger and calibration buffer data.
   7: XIO(AFC.SiteStatus.CalibrationRequest)[OTU(AFCMeter.Calibration.Response.Trigger) OTU(CalibrationMediationPending) ,FLL(0,AFC.Util.Buffer.Calibration[1],6) ];
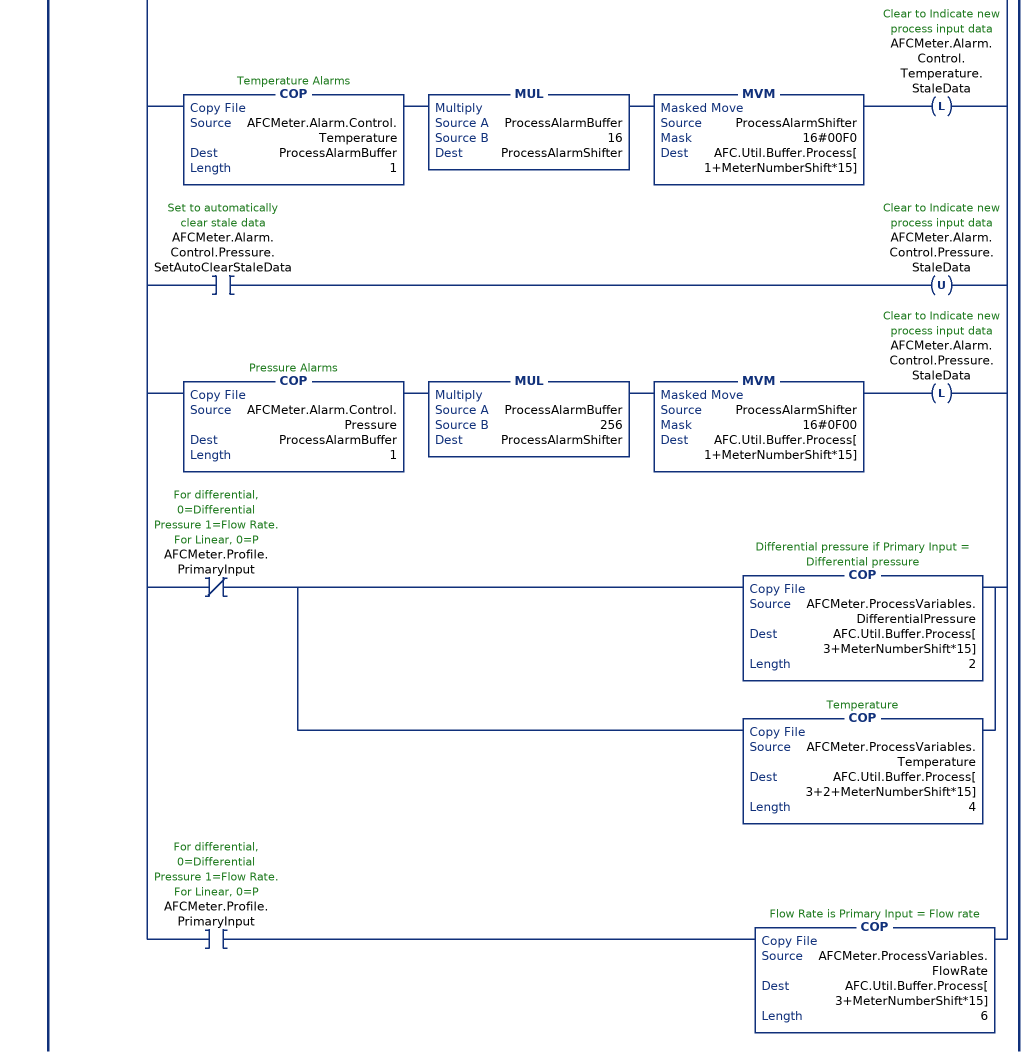
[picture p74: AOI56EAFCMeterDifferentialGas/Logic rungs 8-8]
   // Process variables and process alarms to send to module.
   8: XIC(AFCStopped)[ADD(16#A000,MeterNumber,ProcessInputBlockID) COP(ProcessInputBlockID,AFC.Util.Buffer.Process[MeterNumberShift*15],1) ,[XIO(AFCMeter.Profile.PrimaryInput) XIC(AFCMeter.Alarm.Control.DifferentialPressure.SetAutoClearStaleData) OTU(AFCMeter.Alarm.Control.DifferentialPressure.StaleData) ,XIC(AFCMeter.Profile.PrimaryInput) XIC(AFCMeter.Alarm.Control.FlowRate.SetAutoClearStaleData) OTU(AFCMeter.Alarm.Control.FlowRate.StaleData) ,[XIO(AFCMeter.Profile.PrimaryInput) COP(AFCMeter.Alarm.Control.DifferentialPressure,AFC.Util.Buffer.Process[1+MeterNumberShift*15],1) OTL(AFCMeter.Alarm.Control.DifferentialPressure.StaleData) ,XIC(AFCMeter.Profile.PrimaryInput) COP(AFCMeter.Alarm.Control.FlowRate,AFC.Util.Buffer.Process[1+MeterNumberShift*15],1) OTL(AFCMeter.Alarm.Control.FlowRate.StaleData) ] ] ,[XIC(AFCMeter.Alarm.Control.Temperature.SetAutoClearStaleData) OTU(AFCMeter.Alarm.Control.Temperature.StaleData) ,COP(AFCMeter.Alarm.Control.Temperature,ProcessAlarmBuffer,1) MUL(ProcessAlarmBuffer,16,ProcessAlarmShifter) MVM(ProcessAlarmShifter,16#00F0,AFC.Util.Buffer.Process[1+MeterNumberShift*15]) OTL(AFCMeter.Alarm.Control.Temperature.StaleData) ] ,[XIC(AFCMeter.Alarm.Control.Pressure.SetAutoClearStaleData) OTU(AFCMeter.Alarm.Control.Pressure.StaleData) ,COP(AFCMeter.Alarm.Control.Pressure,ProcessAlarmBuffer,1) MUL(ProcessAlarmBuffer,256,ProcessAlarmShifter) MVM(ProcessAlarmShifter,16#0F00,AFC.Util.Buffer.Process[1+MeterNumberShift*15]) OTL(AFCMeter.Alarm.Control.Pressure.StaleData) ] ,XIO(AFCMeter.Profile.PrimaryInput) [COP(AFCMeter.ProcessVariables.DifferentialPressure,AFC.Util.Buffer.Process[3+MeterNumberShift*15],2) ,COP(AFCMeter.ProcessVariables.Temperature,AFC.Util.Buffer.Process[3+2+MeterNumberShift*15],4) ] ,XIC(AFCMeter.Profile.PrimaryInput) COP(AFCMeter.ProcessVariables.FlowRate,AFC.Util.Buffer.Process[3+MeterNumberShift*15],6) ];
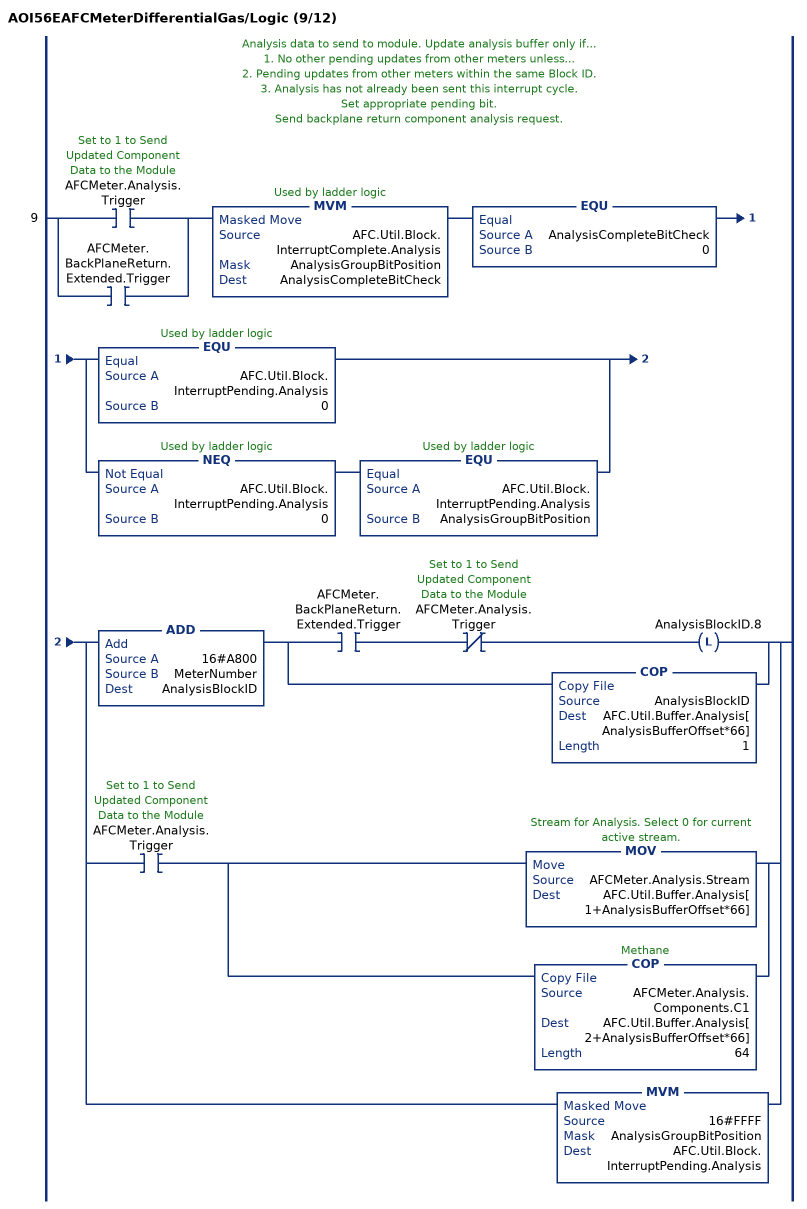
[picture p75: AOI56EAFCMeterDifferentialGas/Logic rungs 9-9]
   // Analysis data to send to module. Update analysis buffer only if...
   // 1. No other pending updates from other meters unless...
   // 2. Pending updates from other meters within the same Block ID.
   // 3. Analysis has not already been sent this interrupt cycle.
   // Set appropriate pending bit.
   // Send backplane return component analysis request.
   9: [XIC(AFCMeter.Analysis.Trigger) ,XIC(AFCMeter.BackPlaneReturn.Extended.Trigger) ]MVM(AFC.Util.Block.InterruptComplete.Analysis,AnalysisGroupBitPosition,AnalysisCompleteBitCheck)EQU(AnalysisCompleteBitCheck,0)[EQU(AFC.Util.Block.InterruptPending.Analysis,0) ,NEQ(AFC.Util.Block.InterruptPending.Analysis,0) EQU(AFC.Util.Block.InterruptPending.Analysis,AnalysisGroupBitPosition) ][ADD(16#A800,MeterNumber,AnalysisBlockID) [XIC(AFCMeter.BackPlaneReturn.Extended.Trigger) XIO(AFCMeter.Analysis.Trigger) OTL(AnalysisBlockID.8) ,COP(AnalysisBlockID,AFC.Util.Buffer.Analysis[AnalysisBufferOffset*66],1) ] ,XIC(AFCMeter.Analysis.Trigger) [MOV(AFCMeter.Analysis.Stream,AFC.Util.Buffer.Analysis[1+AnalysisBufferOffset*66]) ,COP(AFCMeter.Analysis.Components.C1,AFC.Util.Buffer.Analysis[2+AnalysisBufferOffset*66],64) ] ,MVM(16#FFFF,AnalysisGroupBitPosition,AFC.Util.Block.InterruptPending.Analysis) ];
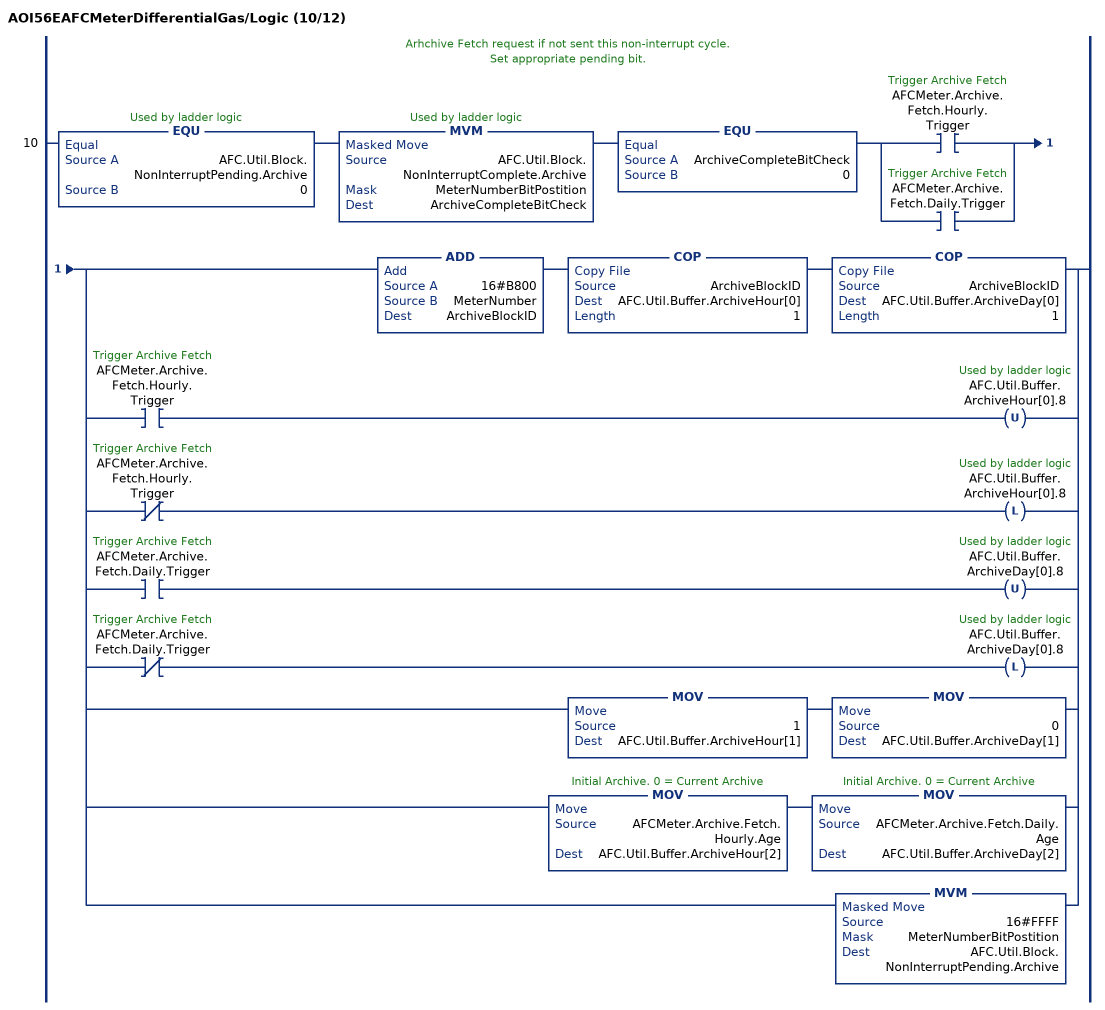
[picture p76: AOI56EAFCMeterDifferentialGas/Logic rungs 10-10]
   // Arhchive Fetch request if not sent this non-interrupt cycle.
   // Set appropriate pending bit.
   10: EQU(AFC.Util.Block.NonInterruptPending.Archive,0)MVM(AFC.Util.Block.NonInterruptComplete.Archive,MeterNumberBitPostition,ArchiveCompleteBitCheck)EQU(ArchiveCompleteBitCheck,0)[XIC(AFCMeter.Archive.Fetch.Hourly.Trigger) ,XIC(AFCMeter.Archive.Fetch.Daily.Trigger) ][ADD(16#B800,MeterNumber,ArchiveBlockID) COP(ArchiveBlockID,AFC.Util.Buffer.ArchiveHour[0],1) COP(ArchiveBlockID,AFC.Util.Buffer.ArchiveDay[0],1) ,[XIC(AFCMeter.Archive.Fetch.Hourly.Trigger) OTU(AFC.Util.Buffer.ArchiveHour[0].8) ,XIO(AFCMeter.Archive.Fetch.Hourly.Trigger) OTL(AFC.Util.Buffer.ArchiveHour[0].8) ] ,[XIC(AFCMeter.Archive.Fetch.Daily.Trigger) OTU(AFC.Util.Buffer.ArchiveDay[0].8) ,XIO(AFCMeter.Archive.Fetch.Daily.Trigger) OTL(AFC.Util.Buffer.ArchiveDay[0].8) ] ,MOV(1,AFC.Util.Buffer.ArchiveHour[1]) MOV(0,AFC.Util.Buffer.ArchiveDay[1]) ,MOV(AFCMeter.Archive.Fetch.Hourly.Age,AFC.Util.Buffer.ArchiveHour[2]) MOV(AFCMeter.Archive.Fetch.Daily.Age,AFC.Util.Buffer.ArchiveDay[2]) ,MVM(16#FFFF,MeterNumberBitPostition,AFC.Util.Block.NonInterruptPending.Archive) ];
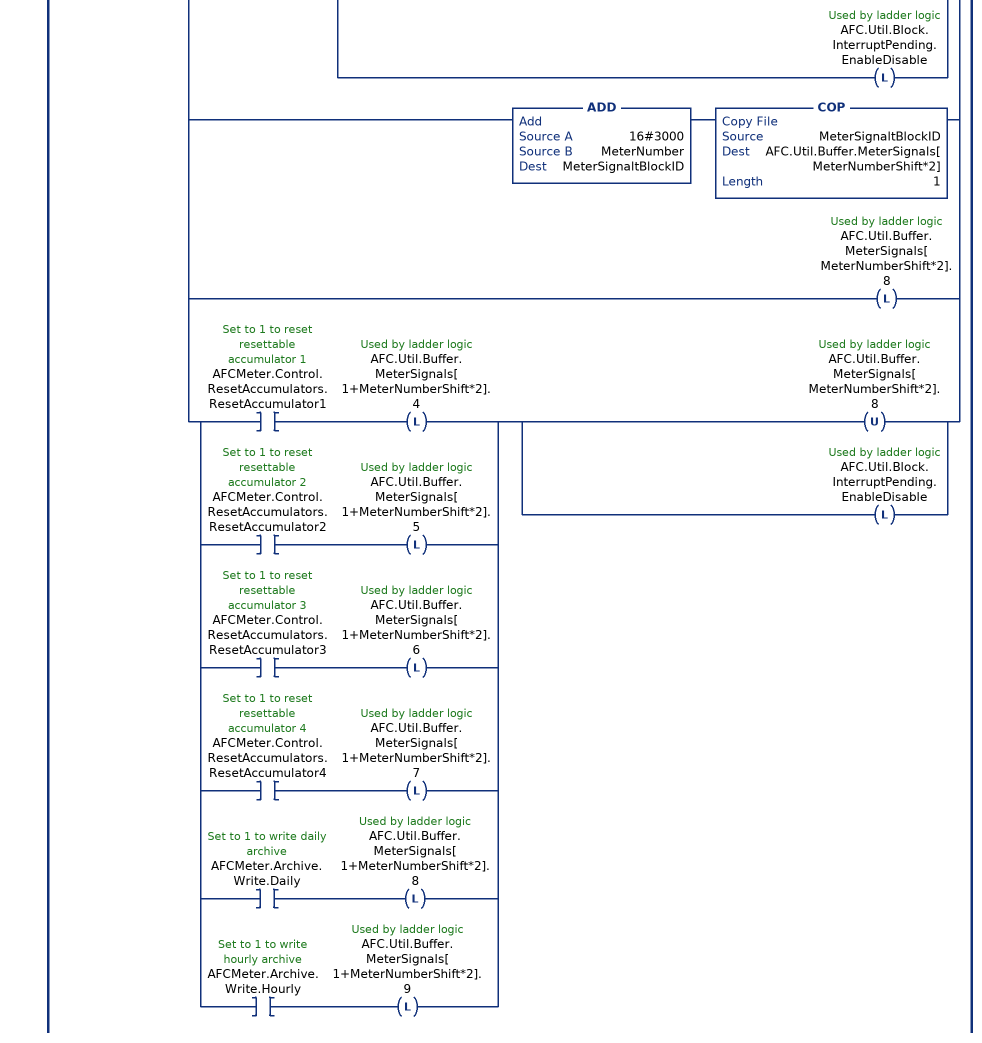
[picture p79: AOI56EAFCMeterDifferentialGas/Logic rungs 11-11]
   // Meter Enable.
   // Meter Disable.
   // Stream Select.
   // Stream Enable.
   // Stream Disable.
   // Set pending bit if not set this interrupt cycle.
   11: XIO(AFC.Util.Block.InterruptComplete.EnableDisable)[LIM(1,AFCMeter.Control.Stream.Selected,16) CPT(StreamEnableBitPosition,2**(AFCMeter.Control.Stream.Selected-1)) ,[XIC(AFCMeter.Control.Meter.Enable) MVM(16#FFFF,MeterNumberBitPostition,AFC.Util.Buffer.MeterEnableDisable[1]) MVM(16#0000,MeterNumberBitPostition,AFC.Util.Buffer.MeterEnableDisable[3]) ,XIC(AFCMeter.Control.Meter.Disable) MVM(16#FFFF,MeterNumberBitPostition,AFC.Util.Buffer.MeterEnableDisable[3]) MVM(16#0000,MeterNumberBitPostition,AFC.Util.Buffer.MeterEnableDisable[1]) ] OTL(AFC.Util.Block.InterruptPending.EnableDisable) ,[ADD(16#CC00,MeterNumber,StreamEnableBlockID) COP(StreamEnableBlockID,AFC.Util.Buffer.StreamEnable[MeterNumberShift*3],1) ,XIO(AFCMeter.Control.Stream.EnableSelected) OTL(AFC.Util.Buffer.StreamEnable[MeterNumberShift*3].8) ,XIC(AFCMeter.Control.Stream.EnableSelected) [OTU(AFC.Util.Buffer.StreamEnable[MeterNumberShift*3].8) ,COP(StreamEnableBitPosition,AFC.Util.Buffer.StreamEnable[1+MeterNumberShift*3],1) ,OTL(AFC.Util.Block.InterruptPending.EnableDisable) ] ] ,[ADD(16#C800,MeterNumber,StreamDisableBlockID) COP(StreamDisableBlockID,AFC.Util.Buffer.StreamDisable[MeterNumberShift*3],1) ,XIO(AFCMeter.Control.Stream.DisableSelected) OTL(AFC.Util.Buffer.StreamDisable[MeterNumberShift*3].8) ,XIC(AFCMeter.Control.Stream.DisableSelected) [OTU(AFC.Util.Buffer.StreamDisable[MeterNumberShift*3].8) ,COP(StreamEnableBitPosition,AFC.Util.Buffer.StreamDisable[1+MeterNumberShift*3],1) ,OTL(AFC.Util.Block.InterruptPending.EnableDisable) ] ] ,[ADD(16#3C00,MeterNumber,StreamSelectBlockID) COP(StreamSelectBlockID,AFC.Util.Buffer.StreamSelect[MeterNumberShift*2],1) ,XIO(AFCMeter.Control.Stream.SetSelectedToActive) OTL(AFC.Util.Buffer.StreamSelect[MeterNumberShift*2].8) ,XIC(AFCMeter.Control.Stream.SetSelectedToActive) [OTU(AFC.Util.Buffer.StreamSelect[MeterNumberShift*2].8) ,MOV(AFCMeter.Control.Stream.Selected,AFC.Util.Buffer.StreamSelect[1+MeterNumberShift*2]) ,OTL(AFC.Util.Block.InterruptPending.EnableDisable) ] ] ,[ADD(16#3000,MeterNumber,MeterSignaltBlockID) COP(MeterSignaltBlockID,AFC.Util.Buffer.MeterSignals[MeterNumberShift*2],1) ,OTL(AFC.Util.Buffer.MeterSignals[MeterNumberShift*2].8) ,[XIC(AFCMeter.Control.ResetAccumulators.ResetAccumulator1) OTL(AFC.Util.Buffer.MeterSignals[1+MeterNumberShift*2].4) ,XIC(AFCMeter.Control.ResetAccumulators.ResetAccumulator2) OTL(AFC.Util.Buffer.MeterSignals[1+MeterNumberShift*2].5) ,XIC(AFCMeter.Control.ResetAccumulators.ResetAccumulator3) OTL(AFC.Util.Buffer.MeterSignals[1+MeterNumberShift*2].6) ,XIC(AFCMeter.Control.ResetAccumulators.ResetAccumulator4) OTL(AFC.Util.Buffer.MeterSignals[1+MeterNumberShift*2].7) ,XIC(AFCMeter.Archive.Write.Daily) OTL(AFC.Util.Buffer.MeterSignals[1+MeterNumberShift*2].8) ,XIC(AFCMeter.Archive.Write.Hourly) OTL(AFC.Util.Buffer.MeterSignals[1+MeterNumberShift*2].9) ] [OTU(AFC.Util.Buffer.MeterSignals[MeterNumberShift*2].8) ,OTL(AFC.Util.Block.InterruptPending.EnableDisable) ] ] ];
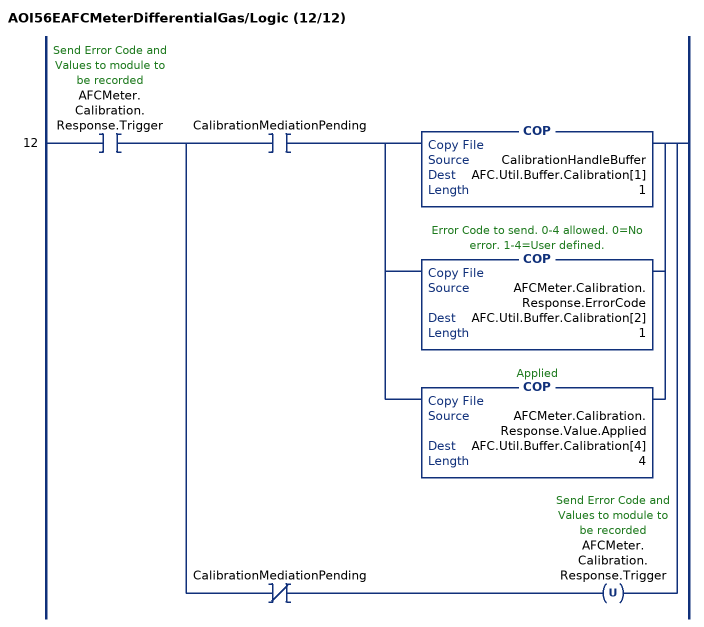
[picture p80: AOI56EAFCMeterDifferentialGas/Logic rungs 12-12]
   12: XIC(AFCMeter.Calibration.Response.Trigger)[XIC(CalibrationMediationPending) [COP(CalibrationHandleBuffer,AFC.Util.Buffer.Calibration[1],1) ,COP(AFCMeter.Calibration.Response.ErrorCode,AFC.Util.Buffer.Calibration[2],1) ,COP(AFCMeter.Calibration.Response.Value.Applied,AFC.Util.Buffer.Calibration[4],4) ] ,XIO(CalibrationMediationPending) OTU(AFCMeter.Calibration.Response.Trigger) ];
END_ROUTINE
(* Logix 5000 project; controller V16_L55_Blank vendor 1 type 14 code 51 rev 16.2; software revision 16.04; part 5 of 5 *)
(* tags used below, declared in another part *)
   ErrorTimer : TIMER;
(* AOI56EAFCNetworkConfig, continued *)

ROUTINE Prescan   (* ladder *)
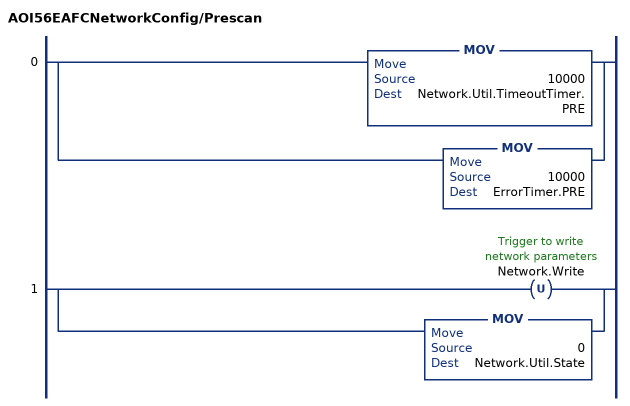
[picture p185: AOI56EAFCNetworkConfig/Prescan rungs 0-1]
   0: [MOV(10000,Network.Util.TimeoutTimer.PRE) ,MOV(10000,ErrorTimer.PRE) ];
   1: [OTU(Network.Write) ,MOV(0,Network.Util.State) ];
END_ROUTINE
END_ADD_ON_INSTRUCTION

VAR_GLOBAL   (* controller tags *)
   AFC : AFCEModuleDef;
   AFCMeter01DifferentialGas : AFCEMeterDifferentialGas;
   AFCMeter02DifferentialLiquid : AFCEMeterDifferentialLiquid;
   AFCMeter03LinearGas : AFCEMeterLinearGas;
   AFCMeter04LinearLiquid : AFCEMeterLinearLiquid;
   AOI56EAFC : AOI56EAFC;
   AOI56EAFCMeter01DifferentialGas : AOI56EAFCMeterDifferentialGas := (MeterNumber := 1);
   AOI56EAFCMeter02DifferentialLiquid : AOI56EAFCMeterDifferentialLiquid := (MeterNumber := 1);
   AOI56EAFCMeter03LinearGas : AOI56EAFCMeterLinearGas;
   AOI56EAFCMeter04LinearLiquid : AOI56EAFCMeterLinearLiquid;
   AOINetworkConfig : AOI56EAFCNetworkConfig;
   Network : AFCENetwork := (Config.Physical_Interface_IP[0] := 192, Config.Physical_Interface_IP[1] := 168, Config.Physical_Interface_IP[3] := 250, Config.Physical_Interface_Network_Prefix := 24, Config.Default_Gateway_IP[0] := 192, Config.Default_Gateway_IP[1] := 168, Config.Default_Gateway_IP[3] := 1, Config.Server1_Network_Prefix := 24, Config.Server1_MBAP_Port := 502, Config.Server1_Listener_IP[0] := 192, Config.Server1_Listener_IP[1] := 168, Config.Server1_Listener_IP[3] := 251);
END_VAR

PROGRAM MainProgram   (* main routine MainRoutine *)

ROUTINE MainRoutine   (* ladder *)
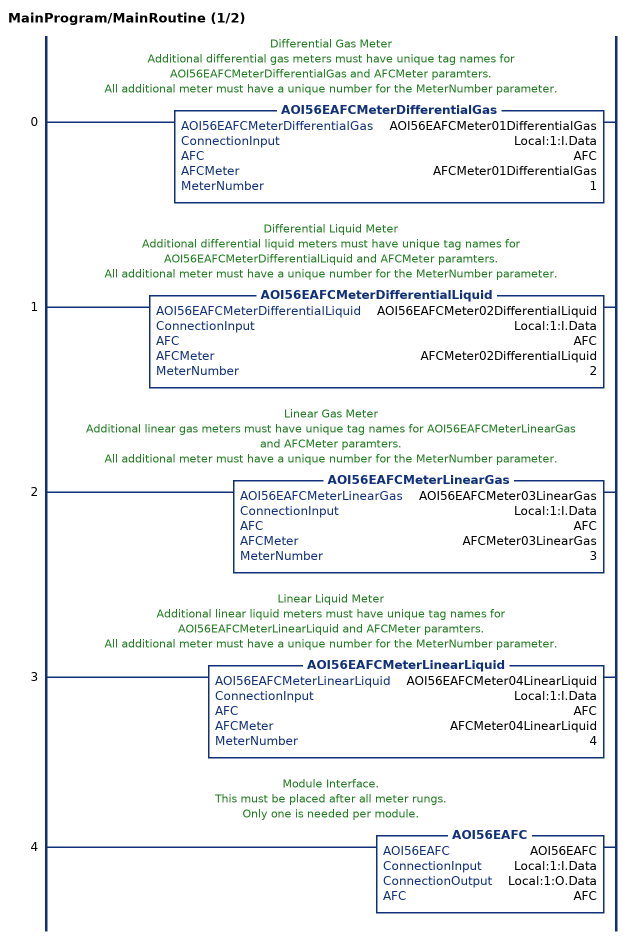
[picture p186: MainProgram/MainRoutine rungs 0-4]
   // Differential Gas Meter
   // Additional differential gas meters must have unique tag names for AOI56EAFCMeterDifferentialGas and AFCMeter paramters.
   // All additional meter must have a unique number for the MeterNumber parameter.
   0: AOI56EAFCMeterDifferentialGas(AOI56EAFCMeter01DifferentialGas,Local:1:I.Data,AFC,AFCMeter01DifferentialGas,1);
   // Differential Liquid Meter
   // Additional differential liquid meters must have unique tag names for AOI56EAFCMeterDifferentialLiquid and AFCMeter paramters.
   // All additional meter must have a unique number for the MeterNumber parameter.
   1: AOI56EAFCMeterDifferentialLiquid(AOI56EAFCMeter02DifferentialLiquid,Local:1:I.Data,AFC,AFCMeter02DifferentialLiquid,2);
   // Linear Gas Meter
   // Additional linear gas meters must have unique tag names for AOI56EAFCMeterLinearGas and AFCMeter paramters.
   // All additional meter must have a unique number for the MeterNumber parameter.
   2: AOI56EAFCMeterLinearGas(AOI56EAFCMeter03LinearGas,Local:1:I.Data,AFC,AFCMeter03LinearGas,3);
   // Linear Liquid Meter
   // Additional linear liquid meters must have unique tag names for AOI56EAFCMeterLinearLiquid and AFCMeter paramters.
   // All additional meter must have a unique number for the MeterNumber parameter.
   3: AOI56EAFCMeterLinearLiquid(AOI56EAFCMeter04LinearLiquid,Local:1:I.Data,AFC,AFCMeter04LinearLiquid,4);
   // Module Interface.
   // This must be placed after all meter rungs.
   // Only one is needed per module.
   4: AOI56EAFC(AOI56EAFC,Local:1:I.Data,Local:1:O.Data,AFC);
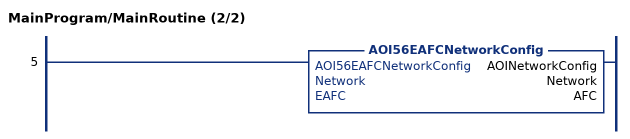
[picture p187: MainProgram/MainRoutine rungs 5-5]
   5: AOI56EAFCNetworkConfig(AOINetworkConfig,Network,AFC);
END_ROUTINE
END_PROGRAM
